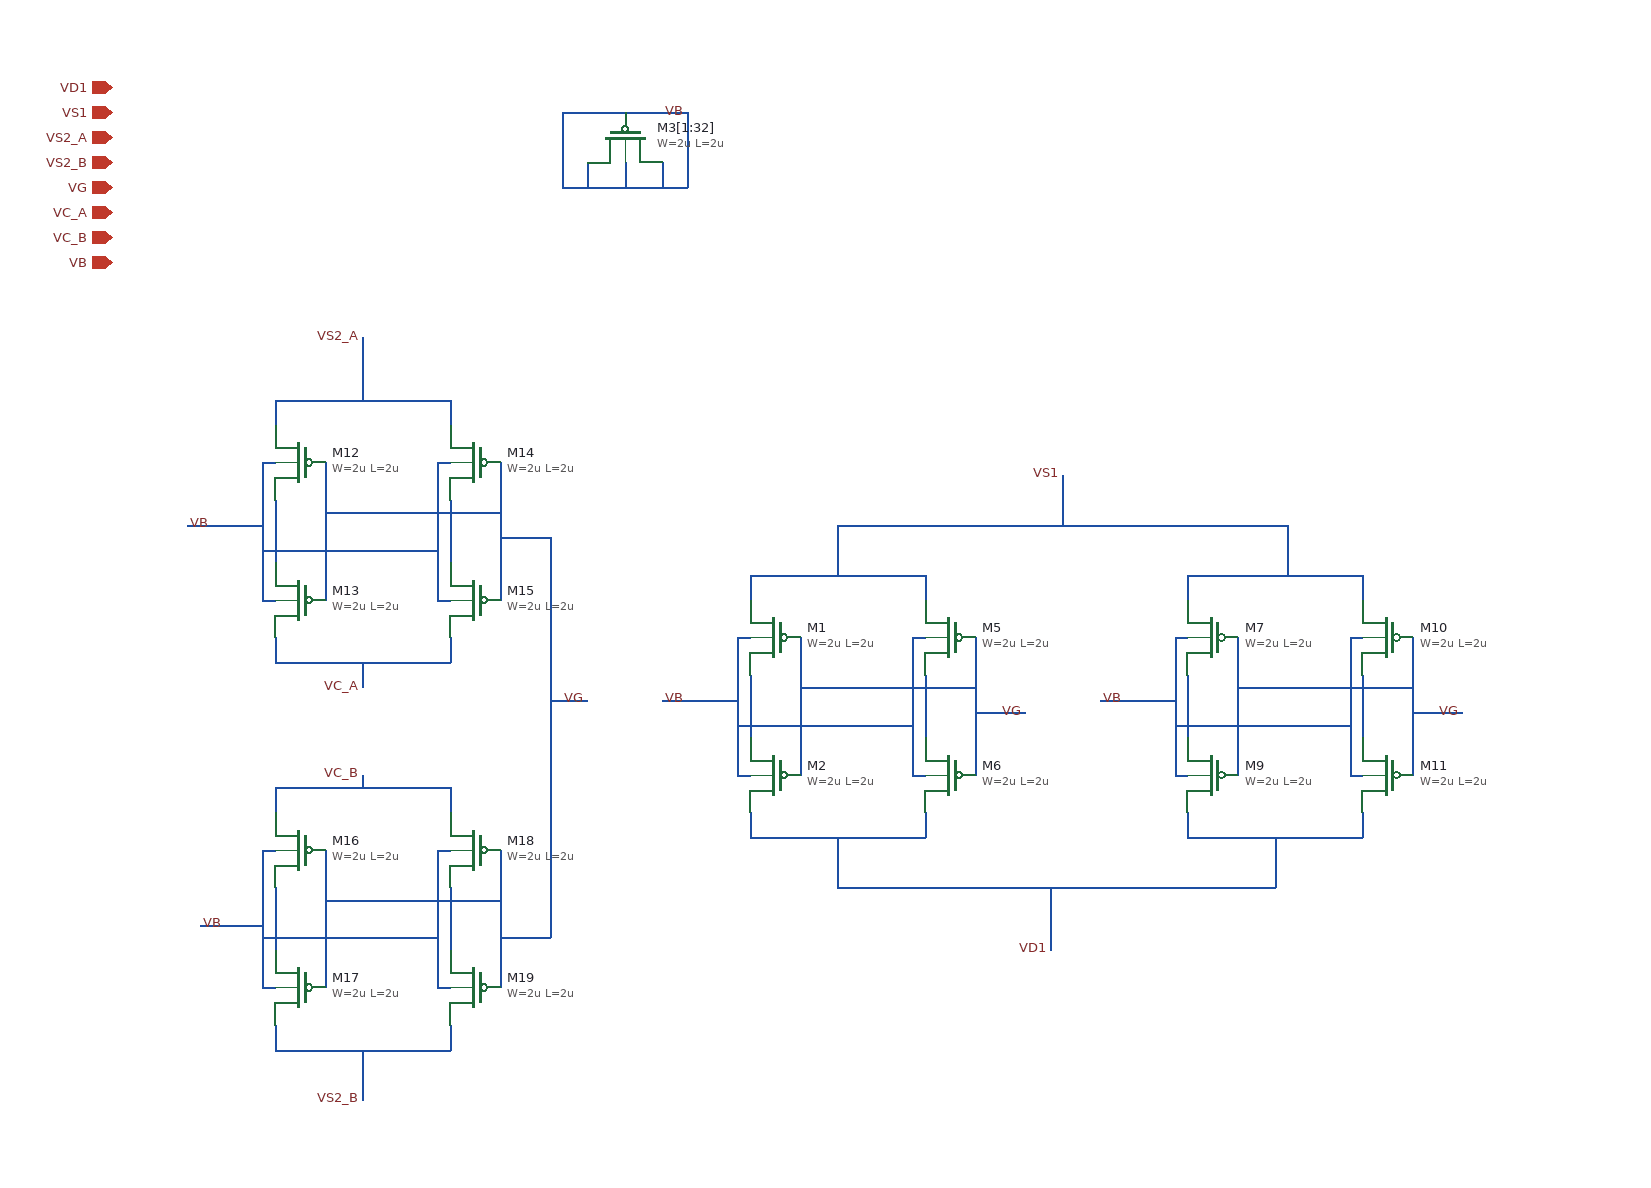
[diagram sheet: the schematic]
v {xschem version=3.4.5 file_version=1.2
}
G {}
K {}
V {}
S {}
E {}
N -80 -310 -80 -260 {
lab=#net1}
N 60 -310 60 -260 {
lab=#net2}
N -80 -390 -80 -370 {
lab=VS2_A}
N -80 -390 60 -390 {
lab=VS2_A}
N 60 -390 60 -370 {
lab=VS2_A}
N -40 -340 -40 -230 {
lab=VG}
N 100 -340 100 -230 {
lab=VG}
N -40 -300 100 -300 {
lab=VG}
N -90 -230 -80 -230 {
lab=VBpr}
N -90 -340 -90 -230 {
lab=VBpr}
N -90 -340 -80 -340 {
lab=VBpr}
N 50 -340 60 -340 {
lab=VBpr}
N 50 -340 50 -230 {
lab=VBpr}
N 50 -230 60 -230 {
lab=VBpr}
N -90 -270 50 -270 {
lab=VBpr}
N -80 -200 -80 -180 {
lab=VC_A}
N -80 -180 60 -180 {
lab=VC_A}
N 60 -200 60 -180 {
lab=VC_A}
N -80 -80 -80 -60 {
lab=VC_B}
N 60 -80 60 -60 {
lab=VC_B}
N 50 -30 60 -30 {
lab=VBpr}
N -90 40 50 40 {
lab=VBpr}
N -80 110 -80 130 {
lab=VS2_B}
N 60 110 60 130 {
lab=VS2_B}
N -90 80 -80 80 {
lab=VBpr}
N -90 -30 -80 -30 {
lab=VBpr}
N 50 80 60 80 {
lab=VBpr}
N -40 10 100 10 {
lab=VG}
N 100 -280 140 -280 {
lab=VG}
N 140 -280 140 0 {
lab=VG}
N 140 -150 170 -150 {
lab=VG}
N -10 -180 -10 -170 {
lab=VC_A}
N 140 0 140 40 {
lab=VG}
N 100 40 140 40 {
lab=VG}
N -150 -290 -90 -290 {
lab=VBpr}
N -140 30 -90 30 {
lab=VBpr}
N 300 -170 300 -120 {
lab=#net3}
N 440 -170 440 -120 {
lab=#net4}
N 300 -250 300 -230 {
lab=VS1}
N 300 -250 440 -250 {
lab=VS1}
N 440 -250 440 -230 {
lab=VS1}
N 340 -200 340 -90 {
lab=VG}
N 480 -200 480 -90 {
lab=VG}
N 340 -160 480 -160 {
lab=VG}
N 290 -90 300 -90 {
lab=VB}
N 290 -200 290 -90 {
lab=VB}
N 290 -200 300 -200 {
lab=VB}
N 430 -200 440 -200 {
lab=VB}
N 430 -200 430 -90 {
lab=VB}
N 430 -90 440 -90 {
lab=VB}
N 290 -130 430 -130 {
lab=VB}
N 300 -60 300 -40 {
lab=VD1}
N 300 -40 440 -40 {
lab=VD1}
N 440 -60 440 -40 {
lab=VD1}
N 480 -140 520 -140 {
lab=VG}
N 370 -40 370 -30 {
lab=VD1}
N 370 -30 370 -10 {
lab=VD1}
N 230 -150 290 -150 {
lab=VB}
N 650 -170 650 -120 {
lab=#net5}
N 790 -170 790 -120 {
lab=#net6}
N 650 -250 650 -230 {
lab=VS1}
N 650 -250 790 -250 {
lab=VS1}
N 790 -250 790 -230 {
lab=VS1}
N 690 -200 690 -90 {
lab=VG}
N 830 -200 830 -90 {
lab=VG}
N 690 -160 830 -160 {
lab=VG}
N 640 -90 650 -90 {
lab=VB}
N 640 -200 640 -90 {
lab=VB}
N 640 -200 650 -200 {
lab=VB}
N 780 -200 790 -200 {
lab=VB}
N 780 -200 780 -90 {
lab=VB}
N 780 -90 790 -90 {
lab=VB}
N 640 -130 780 -130 {
lab=VB}
N 650 -60 650 -40 {
lab=VD1}
N 650 -40 790 -40 {
lab=VD1}
N 790 -60 790 -40 {
lab=VD1}
N 830 -140 870 -140 {
lab=VG}
N 720 -40 720 -30 {
lab=VD1}
N 720 -30 720 -10 {
lab=VD1}
N 580 -150 640 -150 {
lab=VB}
N 370 -290 370 -250 {
lab=VS1}
N 370 -290 730 -290 {
lab=VS1}
N 730 -290 730 -250 {
lab=VS1}
N 550 -330 550 -290 {
lab=VS1}
N 370 -10 370 0 {
lab=VD1}
N 370 -0 720 0 {
lab=VD1}
N 720 -10 720 0 {
lab=VD1}
N 540 0 540 50 {
lab=VD1}
N -10 -440 -10 -390 {
lab=VS2_A}
N -10 130 -10 170 {
lab=VS2_B}
N 150 -620 200 -620 {
lab=VB}
N 150 -620 150 -560 {
lab=VB}
N 150 -560 250 -560 {
lab=VB}
N 250 -620 250 -560 {
lab=VB}
N 200 -620 250 -620 {
lab=VB}
N 230 -580 230 -560 {
lab=VB}
N 200 -580 200 -560 {
lab=VB}
N 170 -580 170 -560 {
lab=VB}
N -10 -170 -10 -160 {
lab=VC_A}
N -10 -90 -10 -80 {
lab=VC_B}
N -80 -80 60 -80 {
lab=VC_B}
N 50 -30 50 80 {
lab=VBpr}
N -90 -30 -90 80 {
lab=VBpr}
N 100 -30 100 80 {
lab=VG}
N -80 130 60 130 {
lab=VS2_B}
N -80 0 -80 50 {
lab=#net7}
N 60 0 60 50 {
lab=#net8}
N -40 -30 -40 80 {
lab=VG}
C {symbols/pfet_03v3.sym} 320 -200 0 1 {name=M1
L=2u
W=2u
nf=1
m=1
ad="'int((nf+1)/2) * W/nf * 0.18u'"
pd="'2*int((nf+1)/2) * (W/nf + 0.18u)'"
as="'int((nf+2)/2) * W/nf * 0.18u'"
ps="'2*int((nf+2)/2) * (W/nf + 0.18u)'"
nrd="'0.18u / W'" nrs="'0.18u / W'"
sa=0 sb=0 sd=0
model=pfet_03v3
spiceprefix=X
}
C {symbols/pfet_03v3.sym} 320 -90 0 1 {name=M2
L=2u
W=2u
nf=1
m=1
ad="'int((nf+1)/2) * W/nf * 0.18u'"
pd="'2*int((nf+1)/2) * (W/nf + 0.18u)'"
as="'int((nf+2)/2) * W/nf * 0.18u'"
ps="'2*int((nf+2)/2) * (W/nf + 0.18u)'"
nrd="'0.18u / W'" nrs="'0.18u / W'"
sa=0 sb=0 sd=0
model=pfet_03v3
spiceprefix=X
}
C {symbols/pfet_03v3.sym} 460 -200 0 1 {name=M5
L=2u
W=2u
nf=1
m=1
ad="'int((nf+1)/2) * W/nf * 0.18u'"
pd="'2*int((nf+1)/2) * (W/nf + 0.18u)'"
as="'int((nf+2)/2) * W/nf * 0.18u'"
ps="'2*int((nf+2)/2) * (W/nf + 0.18u)'"
nrd="'0.18u / W'" nrs="'0.18u / W'"
sa=0 sb=0 sd=0
model=pfet_03v3
spiceprefix=X
}
C {symbols/pfet_03v3.sym} 460 -90 0 1 {name=M6
L=2u
W=2u
nf=1
m=1
ad="'int((nf+1)/2) * W/nf * 0.18u'"
pd="'2*int((nf+1)/2) * (W/nf + 0.18u)'"
as="'int((nf+2)/2) * W/nf * 0.18u'"
ps="'2*int((nf+2)/2) * (W/nf + 0.18u)'"
nrd="'0.18u / W'" nrs="'0.18u / W'"
sa=0 sb=0 sd=0
model=pfet_03v3
spiceprefix=X
}
C {symbols/pfet_03v3.sym} 670 -200 0 1 {name=M7
L=2u
W=2u
nf=1
m=1
ad="'int((nf+1)/2) * W/nf * 0.18u'"
pd="'2*int((nf+1)/2) * (W/nf + 0.18u)'"
as="'int((nf+2)/2) * W/nf * 0.18u'"
ps="'2*int((nf+2)/2) * (W/nf + 0.18u)'"
nrd="'0.18u / W'" nrs="'0.18u / W'"
sa=0 sb=0 sd=0
model=pfet_03v3
spiceprefix=X
}
C {symbols/pfet_03v3.sym} 670 -90 0 1 {name=M9
L=2u
W=2u
nf=1
m=1
ad="'int((nf+1)/2) * W/nf * 0.18u'"
pd="'2*int((nf+1)/2) * (W/nf + 0.18u)'"
as="'int((nf+2)/2) * W/nf * 0.18u'"
ps="'2*int((nf+2)/2) * (W/nf + 0.18u)'"
nrd="'0.18u / W'" nrs="'0.18u / W'"
sa=0 sb=0 sd=0
model=pfet_03v3
spiceprefix=X
}
C {symbols/pfet_03v3.sym} 810 -200 0 1 {name=M10
L=2u
W=2u
nf=1
m=1
ad="'int((nf+1)/2) * W/nf * 0.18u'"
pd="'2*int((nf+1)/2) * (W/nf + 0.18u)'"
as="'int((nf+2)/2) * W/nf * 0.18u'"
ps="'2*int((nf+2)/2) * (W/nf + 0.18u)'"
nrd="'0.18u / W'" nrs="'0.18u / W'"
sa=0 sb=0 sd=0
model=pfet_03v3
spiceprefix=X
}
C {symbols/pfet_03v3.sym} 810 -90 0 1 {name=M11
L=2u
W=2u
nf=1
m=1
ad="'int((nf+1)/2) * W/nf * 0.18u'"
pd="'2*int((nf+1)/2) * (W/nf + 0.18u)'"
as="'int((nf+2)/2) * W/nf * 0.18u'"
ps="'2*int((nf+2)/2) * (W/nf + 0.18u)'"
nrd="'0.18u / W'" nrs="'0.18u / W'"
sa=0 sb=0 sd=0
model=pfet_03v3
spiceprefix=X
}
C {symbols/pfet_03v3.sym} -60 -340 0 1 {name=M12
L=2u
W=2u
nf=1
m=1
ad="'int((nf+1)/2) * W/nf * 0.18u'"
pd="'2*int((nf+1)/2) * (W/nf + 0.18u)'"
as="'int((nf+2)/2) * W/nf * 0.18u'"
ps="'2*int((nf+2)/2) * (W/nf + 0.18u)'"
nrd="'0.18u / W'" nrs="'0.18u / W'"
sa=0 sb=0 sd=0
model=pfet_03v3
spiceprefix=X
}
C {symbols/pfet_03v3.sym} -60 -230 0 1 {name=M13
L=2u
W=2u
nf=1
m=1
ad="'int((nf+1)/2) * W/nf * 0.18u'"
pd="'2*int((nf+1)/2) * (W/nf + 0.18u)'"
as="'int((nf+2)/2) * W/nf * 0.18u'"
ps="'2*int((nf+2)/2) * (W/nf + 0.18u)'"
nrd="'0.18u / W'" nrs="'0.18u / W'"
sa=0 sb=0 sd=0
model=pfet_03v3
spiceprefix=X
}
C {symbols/pfet_03v3.sym} 80 -340 0 1 {name=M14
L=2u
W=2u
nf=1
m=1
ad="'int((nf+1)/2) * W/nf * 0.18u'"
pd="'2*int((nf+1)/2) * (W/nf + 0.18u)'"
as="'int((nf+2)/2) * W/nf * 0.18u'"
ps="'2*int((nf+2)/2) * (W/nf + 0.18u)'"
nrd="'0.18u / W'" nrs="'0.18u / W'"
sa=0 sb=0 sd=0
model=pfet_03v3
spiceprefix=X
}
C {symbols/pfet_03v3.sym} 80 -230 0 1 {name=M15
L=2u
W=2u
nf=1
m=1
ad="'int((nf+1)/2) * W/nf * 0.18u'"
pd="'2*int((nf+1)/2) * (W/nf + 0.18u)'"
as="'int((nf+2)/2) * W/nf * 0.18u'"
ps="'2*int((nf+2)/2) * (W/nf + 0.18u)'"
nrd="'0.18u / W'" nrs="'0.18u / W'"
sa=0 sb=0 sd=0
model=pfet_03v3
spiceprefix=X
}
C {symbols/pfet_03v3.sym} -60 -30 2 0 {name=M16
L=2u
W=2u
nf=1
m=1
ad="'int((nf+1)/2) * W/nf * 0.18u'"
pd="'2*int((nf+1)/2) * (W/nf + 0.18u)'"
as="'int((nf+2)/2) * W/nf * 0.18u'"
ps="'2*int((nf+2)/2) * (W/nf + 0.18u)'"
nrd="'0.18u / W'" nrs="'0.18u / W'"
sa=0 sb=0 sd=0
model=pfet_03v3
spiceprefix=X
}
C {symbols/pfet_03v3.sym} -60 80 2 0 {name=M17
L=2u
W=2u
nf=1
m=1
ad="'int((nf+1)/2) * W/nf * 0.18u'"
pd="'2*int((nf+1)/2) * (W/nf + 0.18u)'"
as="'int((nf+2)/2) * W/nf * 0.18u'"
ps="'2*int((nf+2)/2) * (W/nf + 0.18u)'"
nrd="'0.18u / W'" nrs="'0.18u / W'"
sa=0 sb=0 sd=0
model=pfet_03v3
spiceprefix=X
}
C {symbols/pfet_03v3.sym} 80 -30 2 0 {name=M18
L=2u
W=2u
nf=1
m=1
ad="'int((nf+1)/2) * W/nf * 0.18u'"
pd="'2*int((nf+1)/2) * (W/nf + 0.18u)'"
as="'int((nf+2)/2) * W/nf * 0.18u'"
ps="'2*int((nf+2)/2) * (W/nf + 0.18u)'"
nrd="'0.18u / W'" nrs="'0.18u / W'"
sa=0 sb=0 sd=0
model=pfet_03v3
spiceprefix=X
}
C {symbols/pfet_03v3.sym} 80 80 2 0 {name=M19
L=2u
W=2u
nf=1
m=1
ad="'int((nf+1)/2) * W/nf * 0.18u'"
pd="'2*int((nf+1)/2) * (W/nf + 0.18u)'"
as="'int((nf+2)/2) * W/nf * 0.18u'"
ps="'2*int((nf+2)/2) * (W/nf + 0.18u)'"
nrd="'0.18u / W'" nrs="'0.18u / W'"
sa=0 sb=0 sd=0
model=pfet_03v3
spiceprefix=X
}
C {devices/iopin.sym} -210 -640 0 0 {name=p1 lab=VD1}
C {devices/iopin.sym} -210 -620 0 0 {name=p2 lab=VS1}
C {devices/iopin.sym} -210 -600 0 0 {name=p3 lab=VS2_A}
C {devices/iopin.sym} -210 -580 0 0 {name=p4 lab=VS2_B}
C {devices/iopin.sym} -210 -560 0 0 {name=p5 lab=VG}
C {devices/iopin.sym} -210 -540 0 0 {name=p6 lab=VC_A}
C {devices/iopin.sym} -210 -520 0 0 {name=p7 lab=VC_B}
C {devices/iopin.sym} -210 -500 0 0 {name=p8 lab=VB}
C {symbols/pfet_03v3.sym} 200 -600 3 1 {name=M3[1:32]
L=2u
W=2u
nf=1
m=1
ad="'int((nf+1)/2) * W/nf * 0.18u'"
pd="'2*int((nf+1)/2) * (W/nf + 0.18u)'"
as="'int((nf+2)/2) * W/nf * 0.18u'"
ps="'2*int((nf+2)/2) * (W/nf + 0.18u)'"
nrd="'0.18u / W'" nrs="'0.18u / W'"
sa=0 sb=0 sd=0
model=pfet_03v3
spiceprefix=X
}
C {devices/lab_wire.sym} 250 -620 0 0 {name=p9 sig_type=std_logic lab=VB}
C {devices/lab_wire.sym} 540 50 0 0 {name=p13 sig_type=std_logic lab=VD1
L=2u
W=2u}
C {devices/lab_wire.sym} 550 -330 0 0 {name=p10 sig_type=std_logic lab=VS1
L=2u
W=2u}
C {devices/lab_wire.sym} 520 -140 0 0 {name=p11 sig_type=std_logic lab=VG
L=2u
W=2u}
C {devices/lab_wire.sym} 870 -140 0 0 {name=p12 sig_type=std_logic lab=VG
L=2u
W=2u}
C {devices/lab_wire.sym} 170 -150 0 0 {name=p14 sig_type=std_logic lab=VG
L=2u
W=2u}
C {devices/lab_wire.sym} 250 -150 0 0 {name=p15 sig_type=std_logic lab=VB
L=2u
W=2u}
C {devices/lab_wire.sym} 600 -150 0 0 {name=p16 sig_type=std_logic lab=VB
L=2u
W=2u}
C {devices/lab_wire.sym} -120 30 0 0 {name=p17 sig_type=std_logic lab=VB

}
C {devices/lab_wire.sym} -130 -290 0 0 {name=p18 sig_type=std_logic lab=VB

}
C {devices/lab_wire.sym} -10 -440 0 0 {name=p19 sig_type=std_logic lab=VS2_A
L=2u
W=2u}
C {devices/lab_wire.sym} -10 170 0 0 {name=p20 sig_type=std_logic lab=VS2_B
L=2u
W=2u}
C {devices/lab_wire.sym} -10 -160 0 0 {name=p21 sig_type=std_logic lab=VC_A
L=2u
W=2u}
C {devices/lab_wire.sym} -10 -90 0 0 {name=p22 sig_type=std_logic lab=VC_B
L=2u
W=2u}
